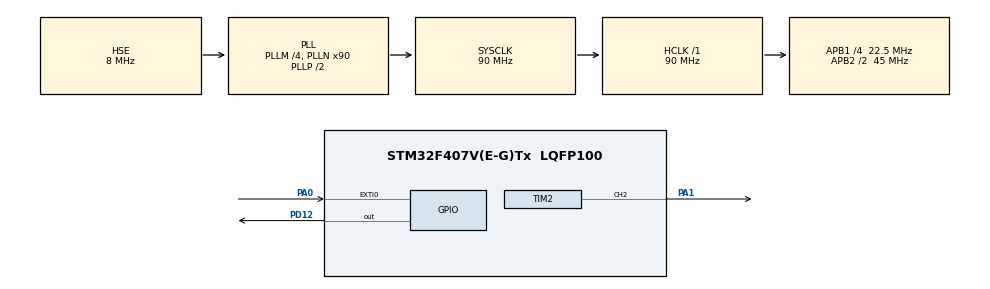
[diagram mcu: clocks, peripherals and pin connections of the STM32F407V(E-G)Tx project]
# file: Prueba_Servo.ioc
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Mcu.Family=STM32F4
Mcu.Name=STM32F407V(E-G)Tx
Mcu.Package=LQFP100
NVIC.EXTI0_IRQn=true\:0\:0\:false\:false\:true\:true\:true
NVIC.PriorityGroup=NVIC_PRIORITYGROUP_0
NVIC.TIM1_UP_TIM10_IRQn=true\:0\:0\:false\:false\:true\:false\:true
NVIC.TIM2_IRQn=true\:0\:0\:false\:false\:true\:true\:true
NVIC.TimeBase=TIM1_UP_TIM10_IRQn
NVIC.TimeBaseIP=TIM1
PA0-WKUP.Signal=GPXTI0
PA1.Signal=S_TIM2_CH2
PC14-OSC32_IN.Mode=LSE-External-Oscillator
PC14-OSC32_IN.Signal=RCC_OSC32_IN
PC15-OSC32_OUT.Mode=LSE-External-Oscillator
PC15-OSC32_OUT.Signal=RCC_OSC32_OUT
PD12.Signal=GPIO_Output
PH0-OSC_IN.Mode=HSE-External-Oscillator
PH0-OSC_IN.Signal=RCC_OSC_IN
PH1-OSC_OUT.Mode=HSE-External-Oscillator
PH1-OSC_OUT.Signal=RCC_OSC_OUT
ProjectManager.HeapSize=0x200
ProjectManager.StackSize=0x400
ProjectManager.TargetToolchain=STM32CubeIDE
RCC.48MHZClocksFreq_Value=25714285.714285713
RCC.AHBFreq_Value=90000000
RCC.APB1CLKDivider=RCC_HCLK_DIV4
RCC.APB1Freq_Value=22500000
RCC.APB1TimFreq_Value=45000000
RCC.APB2CLKDivider=RCC_HCLK_DIV2
RCC.APB2Freq_Value=45000000
RCC.APB2TimFreq_Value=90000000
RCC.CortexFreq_Value=90000000
RCC.HCLKFreq_Value=90000000
RCC.HSE_VALUE=8000000
RCC.HSI_VALUE=16000000
RCC.PLLM=4
RCC.PLLN=90
RCC.PLLQ=7
RCC.PLLSourceVirtual=RCC_PLLSOURCE_HSE
RCC.SYSCLKFreq_VALUE=90000000
RCC.SYSCLKSource=RCC_SYSCLKSOURCE_PLLCLK
RCC.VCOOutputFreq_Value=180000000
SH.S_TIM2_CH2.0=TIM2_CH2,PWM Generation2 CH2
TIM2.Channel-PWM\ Generation2\ CH2=TIM_CHANNEL_2
TIM2.Period=1000-1
TIM2.Prescaler=900-1
VP_SYS_VS_tim1.Mode=TIM1
VP_TIM2_VS_ClockSourceINT.Mode=Internal
board=STM32F407G-DISC1

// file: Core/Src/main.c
/* USER CODE BEGIN Header */
/**
  ******************************************************************************
  * @file           : main.c
  * @brief          : Main program body
  ******************************************************************************
  * @attention
  *
  * <h2><center>&copy; Copyright (c) 2021 STMicroelectronics.
  * All rights reserved.</center></h2>
  *
  * This software component is licensed by ST under Ultimate Liberty license
  * SLA0044, the "License"; You may not use this file except in compliance with
  * the License. You may obtain a copy of the License at:
  *                             www.st.com/SLA0044
  *
  ******************************************************************************
  */
/* USER CODE END Header */
#include "main.h"

TIM_HandleTypeDef htim2;

/* USER CODE BEGIN PV */

volatile int pulsador = 0;
volatile int pulsador1 = 0;

void HAL_GPIO_EXTI_Callback(uint16_t GPIO_Pin)
{
	if(GPIO_Pin == GPIO_PIN_0) {
		pulsador = 1;
	}

	if(GPIO_Pin == GPIO_PIN_3) {
			pulsador1 = 1;
		}
}

int debouncer(volatile int* button_int, GPIO_TypeDef* GPIO_port, uint16_t GPIO_number)
{
	static uint8_t button_count = 0;
	static int counter = 0;

	if(*button_int == 1) {
		if(button_count == 0) {
			counter = HAL_GetTick();
			button_count++;
		}
		if(HAL_GetTick() - counter >= 20) {
			counter = HAL_GetTick();
			if(HAL_GPIO_ReadPin(GPIO_port, GPIO_number) != 1) {
				button_count = 1;
			}
			else {
				button_count++;
			}
			if(button_count == 4) {
				button_count = 0;
				*button_int = 0;
				return 1;
			}
		}
	}
	return 0;
}

void moverServo(TIM_HandleTypeDef* htim, int grados)
{
	const int MAX = 20; // Max valor de frecuencia son 20ms -> 1/50Hz
	float ms = grados/90.0f + 0.5f; // De los valores min y max del servo (0.5ms son 0º, 2.5ms son 180º) -> Ecuacion recta
	float duty = ms/(float)MAX; // Porcentaje del ciclo encendido
	uint32_t CCR = htim->Instance->ARR * duty;	// El valor del CCR es ARR * duty, el ARR es del propio htim
	htim->Instance->CCR2 = CCR; // Se asigna el CCR calculado al CCR2 del htim
}

/* USER CODE END PV */

void SystemClock_Config(void);
static void MX_GPIO_Init(void);
static void MX_TIM2_Init(void);

int main(void)
{

  /* MCU Configuration--------------------------------------------------------*/

  /* Reset of all peripherals, Initializes the Flash interface and the Systick. */
  HAL_Init();

  /* Configure the system clock */
  SystemClock_Config();

  /* Initialize all configured peripherals */
  MX_GPIO_Init();
  MX_TIM2_Init();
  /* USER CODE BEGIN 2 */

  HAL_TIM_PWM_Start(&htim2, TIM_CHANNEL_2);

  /* USER CODE END 2 */

  /* Infinite loop */
  while (1)
  {

    /* USER CODE BEGIN 3 */

	  if(debouncer(&pulsador1, GPIOC, GPIO_PIN_3) || debouncer(&pulsador, GPIOA, GPIO_PIN_0)) {
		  pulsador1 = 0;
		  pulsador = 0;
		  HAL_GPIO_WritePin(GPIOC, GPIO_PIN_6, 1);
		  HAL_Delay(500);
		  HAL_GPIO_WritePin(GPIOC, GPIO_PIN_6, 0);

		  moverServo(&htim2, 0); // Mueve el servo que esta en htim2, X grados
		  HAL_Delay(1000);

		  moverServo(&htim2, 45);
		  HAL_Delay(1000);

		  moverServo(&htim2, 90);
		  HAL_Delay(1000);

		  moverServo(&htim2, 135);
		  HAL_Delay(1000);

		  moverServo(&htim2, 180);
		  HAL_Delay(1000);

		  for(int i = 0; i < 180; i++)
		  {
			  moverServo(&htim2, i);
			  HAL_Delay(25);
		  }

		  for(int i = 180; i > 0; i--)
		  {
		  	  moverServo(&htim2, i);
		  	  HAL_Delay(25);
		  }

		  /*
		  htim2.Instance->CCR2 = 25;
		  HAL_Delay(1000);

		  htim2.Instance->CCR2 = 75;
		  HAL_Delay(1000);

		  htim2.Instance->CCR2 = 125;
		  HAL_Delay(1000);

		  htim2.Instance->CCR2 = 25;

		  int i = 25;
		  HAL_Delay(1000);
		  while(i < 126) {
			  HAL_GPIO_WritePin(GPIOD, GPIO_PIN_12, 1);
			  htim2.Instance->CCR2 = i;
			  i++;
			  HAL_Delay(50);
		  }
		  HAL_Delay(1000);

		  int j = 125;
		  while(j > 24) {
			  HAL_GPIO_WritePin(GPIOD, GPIO_PIN_12, 0);
			  htim2.Instance->CCR2 = j;
			  j--;
			  HAL_Delay(50);
		  }
		  HAL_Delay(1000);
		  */
	  }

  }
  /* USER CODE END 3 */
}

void SystemClock_Config(void)
{
  RCC_OscInitTypeDef RCC_OscInitStruct = {0};
  RCC_ClkInitTypeDef RCC_ClkInitStruct = {0};

  /** Configure the main internal regulator output voltage
  */
  __HAL_RCC_PWR_CLK_ENABLE();
  __HAL_PWR_VOLTAGESCALING_CONFIG(PWR_REGULATOR_VOLTAGE_SCALE1);
  /** Initializes the RCC Oscillators according to the specified parameters
  * in the RCC_OscInitTypeDef structure.
  */
  RCC_OscInitStruct.OscillatorType = RCC_OSCILLATORTYPE_HSE;
  RCC_OscInitStruct.HSEState = RCC_HSE_ON;
  RCC_OscInitStruct.PLL.PLLState = RCC_PLL_ON;
  RCC_OscInitStruct.PLL.PLLSource = RCC_PLLSOURCE_HSE;
  RCC_OscInitStruct.PLL.PLLM = 4;
  RCC_OscInitStruct.PLL.PLLN = 90;
  RCC_OscInitStruct.PLL.PLLP = RCC_PLLP_DIV2;
  RCC_OscInitStruct.PLL.PLLQ = 7;
  if (HAL_RCC_OscConfig(&RCC_OscInitStruct) != HAL_OK)
  {
    Error_Handler();
  }
  /** Initializes the CPU, AHB and APB buses clocks
  */
  RCC_ClkInitStruct.ClockType = RCC_CLOCKTYPE_HCLK|RCC_CLOCKTYPE_SYSCLK
                              |RCC_CLOCKTYPE_PCLK1|RCC_CLOCKTYPE_PCLK2;
  RCC_ClkInitStruct.SYSCLKSource = RCC_SYSCLKSOURCE_PLLCLK;
  RCC_ClkInitStruct.AHBCLKDivider = RCC_SYSCLK_DIV1;
  RCC_ClkInitStruct.APB1CLKDivider = RCC_HCLK_DIV4;
  RCC_ClkInitStruct.APB2CLKDivider = RCC_HCLK_DIV2;

  if (HAL_RCC_ClockConfig(&RCC_ClkInitStruct, FLASH_LATENCY_2) != HAL_OK)
  {
    Error_Handler();
  }
}

static void MX_TIM2_Init(void)
{

  TIM_ClockConfigTypeDef sClockSourceConfig = {0};
  TIM_MasterConfigTypeDef sMasterConfig = {0};
  TIM_OC_InitTypeDef sConfigOC = {0};

  htim2.Instance = TIM2;
  htim2.Init.Prescaler = 900-1;
  htim2.Init.CounterMode = TIM_COUNTERMODE_UP;
  htim2.Init.Period = 1000-1;
  htim2.Init.ClockDivision = TIM_CLOCKDIVISION_DIV1;
  htim2.Init.AutoReloadPreload = TIM_AUTORELOAD_PRELOAD_DISABLE;
  if (HAL_TIM_Base_Init(&htim2) != HAL_OK)
  {
    Error_Handler();
  }
  sClockSourceConfig.ClockSource = TIM_CLOCKSOURCE_INTERNAL;
  if (HAL_TIM_ConfigClockSource(&htim2, &sClockSourceConfig) != HAL_OK)
  {
    Error_Handler();
  }
  if (HAL_TIM_PWM_Init(&htim2) != HAL_OK)
  {
    Error_Handler();
  }
  sMasterConfig.MasterOutputTrigger = TIM_TRGO_RESET;
  sMasterConfig.MasterSlaveMode = TIM_MASTERSLAVEMODE_DISABLE;
  if (HAL_TIMEx_MasterConfigSynchronization(&htim2, &sMasterConfig) != HAL_OK)
  {
    Error_Handler();
  }
  sConfigOC.OCMode = TIM_OCMODE_PWM1;
  sConfigOC.Pulse = 0;
  sConfigOC.OCPolarity = TIM_OCPOLARITY_HIGH;
  sConfigOC.OCFastMode = TIM_OCFAST_DISABLE;
  if (HAL_TIM_PWM_ConfigChannel(&htim2, &sConfigOC, TIM_CHANNEL_2) != HAL_OK)
  {
    Error_Handler();
  }
  HAL_TIM_MspPostInit(&htim2);

}

static void MX_GPIO_Init(void)
{
  GPIO_InitTypeDef GPIO_InitStruct = {0};

  /* GPIO Ports Clock Enable */
  __HAL_RCC_GPIOC_CLK_ENABLE();
  __HAL_RCC_GPIOH_CLK_ENABLE();
  __HAL_RCC_GPIOA_CLK_ENABLE();
  __HAL_RCC_GPIOD_CLK_ENABLE();

  /*Configure GPIO pin Output Level */
  HAL_GPIO_WritePin(GPIOD, GPIO_PIN_12, GPIO_PIN_RESET);

  /*Configure GPIO pin Output Level */
  HAL_GPIO_WritePin(GPIOC, GPIO_PIN_6, GPIO_PIN_RESET);

  /*Configure GPIO pin : PC3 */
  GPIO_InitStruct.Pin = GPIO_PIN_3;
  GPIO_InitStruct.Mode = GPIO_MODE_IT_RISING;
  GPIO_InitStruct.Pull = GPIO_NOPULL;
  HAL_GPIO_Init(GPIOC, &GPIO_InitStruct);

  /*Configure GPIO pin : PA0 */
  GPIO_InitStruct.Pin = GPIO_PIN_0;
  GPIO_InitStruct.Mode = GPIO_MODE_IT_RISING;
  GPIO_InitStruct.Pull = GPIO_NOPULL;
  HAL_GPIO_Init(GPIOA, &GPIO_InitStruct);

  /*Configure GPIO pin : PD12 */
  GPIO_InitStruct.Pin = GPIO_PIN_12;
  GPIO_InitStruct.Mode = GPIO_MODE_OUTPUT_PP;
  GPIO_InitStruct.Pull = GPIO_NOPULL;
  GPIO_InitStruct.Speed = GPIO_SPEED_FREQ_LOW;
  HAL_GPIO_Init(GPIOD, &GPIO_InitStruct);

  /*Configure GPIO pin : PC6 */
  GPIO_InitStruct.Pin = GPIO_PIN_6;
  GPIO_InitStruct.Mode = GPIO_MODE_OUTPUT_PP;
  GPIO_InitStruct.Pull = GPIO_NOPULL;
  GPIO_InitStruct.Speed = GPIO_SPEED_FREQ_LOW;
  HAL_GPIO_Init(GPIOC, &GPIO_InitStruct);

  /* EXTI interrupt init*/
  HAL_NVIC_SetPriority(EXTI0_IRQn, 0, 0);
  HAL_NVIC_EnableIRQ(EXTI0_IRQn);

  HAL_NVIC_SetPriority(EXTI3_IRQn, 0, 0);
  HAL_NVIC_EnableIRQ(EXTI3_IRQn);

}

void HAL_TIM_PeriodElapsedCallback(TIM_HandleTypeDef *htim)
{
  if (htim->Instance == TIM1) {
    HAL_IncTick();
  }
}

void Error_Handler(void)
{
  __disable_irq();
  while (1)
  {
  }
}

/************************ (C) COPYRIGHT STMicroelectronics *****END OF FILE****/
